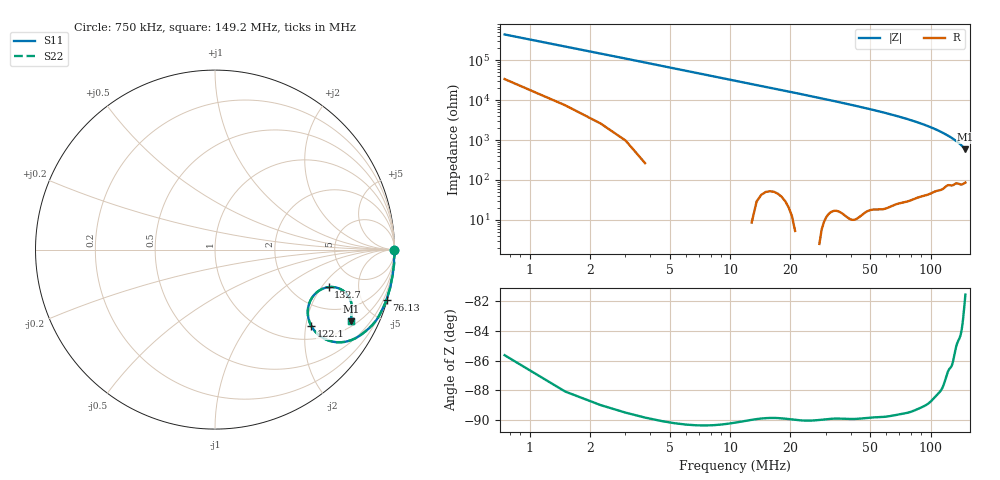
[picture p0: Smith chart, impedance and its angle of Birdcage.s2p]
! Generated by circuitRF - EM: openEMS
! circuitRF-EM setup: Birdcage ReferenceGrid
! circuitRF-EM layout: Birdcage.c3d
! circuitRF-EM written: 2026-10-19 01:58:30Z
! circuitRF-EM geometry: 09e28431972dc2b5
! circuitRF-EM mesh: 625c151b6a92982f
! circuitRF-EM ports: f373557103ee5a10
! circuitRF-EM model: openEMS 0.37.0 (v0.37.0, CSXCAD v0.7.0)
! circuitRF-EM port 1: 'port/1' from 'ringUpper' to 'rung1Upper', lumped, 50 Ohm
! circuitRF-EM port 2: 'port/2' from 'ringUpper' to 'rung3Upper', lumped, 50 Ohm
! circuitRF-EM 3D grid: 65 x 305 x 219 = 4327440 cells; smallest cell 2.4734 mm on ?, set by 'OpenEms.GridLines' given line at ? = 102.6862 mm
! circuitRF-EM 3D openEMS run port 1: dt 3.65071E-13 s (estimate 5.14589E-13 s), 213342 steps, port signals 19.6 dB and energy 41 dB against 40 dB, stopped by openEMS's energy criterion, converged
! circuitRF-EM 3D openEMS run port 2: dt 3.65071E-13 s (estimate 5.14589E-13 s), 213342 steps, port signals 19.6 dB and energy 41 dB against 40 dB, stopped by openEMS's energy criterion, converged
! circuitRF-EM 3D dielectric loss fitted at: 0.075 GHz
! circuitRF-EM 3D perfect conductors: rung1Lower, rung1Upper, rung2Lower, rung2Upper, rung3Lower, rung3Upper, rung4Lower, rung4Upper, rung5Lower, rung5Upper, rung6Lower, rung6Upper, rung7Lower, rung7Upper, rung8Lower, rung8Upper, ringLower, ringUpper
! circuitRF-EM 3D operating temperature: 20 C
! circuitRF-EM 3D port fields: 'Birdcage ReferenceGrid.openems.fields' stamp 20261019T015828Z-2e90cb5e
! circuitRF-EM: re-running the EM setup rewrites this file. If circuitRF reports it as stale, the layout's cross-section changed after this file was written.
# MHz S RI R 50
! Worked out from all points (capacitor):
!   198 points, 750 kHz to 149.2 MHz, reference 50 ohm
!   read as one part in series: C = 477 fF near 750 kHz
!   lowest |Z| = 585 ohm at 149.2 MHz (marker M1)
!   S11 on the Smith chart (normalised r, x): 750 kHz: open; 76.13 MHz: 0.10, -7.01; 122.1 MHz: 1.35, -2.15; 132.7 MHz: 3.12, -2.34; 149.2 MHz: 1.22, -3.64
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0.75  0.9982 -0.00185  1.75e-05 0.000224  1.75e-05 0.000224  0.9982 -0.00185
1.503807  0.9984 -0.00374  1.68e-05 0.000449  1.67e-05 0.000449  0.9984 -0.00374
2.257614  0.9987 -0.00572  1.58e-05 0.000676  1.58e-05 0.000676  0.9987 -0.00572
3.011421  0.9991 -0.00781  1.5e-05 0.000903  1.5e-05 0.000903  0.9991 -0.00781
4.519036  1 -0.0124  1.56e-05 0.00136  1.56e-05 0.00136  1 -0.0124
6.780457  1.001 -0.0203  2.94e-05 0.00207  2.94e-05 0.00207  1.001 -0.0203
9.795685  1.001 -0.0317  8.28e-05 0.00301  8.28e-05 0.00301  1.001 -0.0317
13.56472  0.9986 -0.0443  0.00019 0.00418  0.000191 0.00418  0.9986 -0.0443
25.62563  0.9975 -0.0819  0.000653 0.008  0.000653 0.008  0.9975 -0.0819
50.50127  0.9842 -0.1688  0.0029 0.0166  0.0029 0.0166  0.9842 -0.1688
75.3769  0.9575 -0.2747  0.00802 0.0272  0.00802 0.0272  0.9575 -0.2747
76.13071  0.9562 -0.2786  0.00825 0.0275  0.00825 0.0275  0.9562 -0.2786
100.2525  0.8697 -0.427  0.0199 0.039  0.0199 0.039  0.8697 -0.427
108.5444  0.7942 -0.4872  0.0261 0.0415  0.0261 0.0415  0.7942 -0.4872
114.5749  0.6902 -0.5165  0.0299 0.0409  0.0299 0.0409  0.6902 -0.5165
118.3439  0.6049 -0.4941  0.03 0.0399  0.03 0.0399  0.6049 -0.4941
122.1129  0.5357 -0.4241  0.0275 0.0405  0.0275 0.0405  0.5357 -0.4241
125.1282  0.5169 -0.3445  0.0244 0.0438  0.0244 0.0438  0.5169 -0.3445
128.8972  0.5524 -0.2521  0.0215 0.0523  0.0215 0.0523  0.5524 -0.2521
132.6662  0.6332 -0.2089  0.0226 0.0647  0.0226 0.0647  0.6332 -0.2089
139.4505  0.7503 -0.2711  0.0377 0.0881  0.0377 0.0881  0.7503 -0.2711
149.25  0.7563 -0.4005  0.0787 0.115  0.0787 0.115  0.7563 -0.4005
